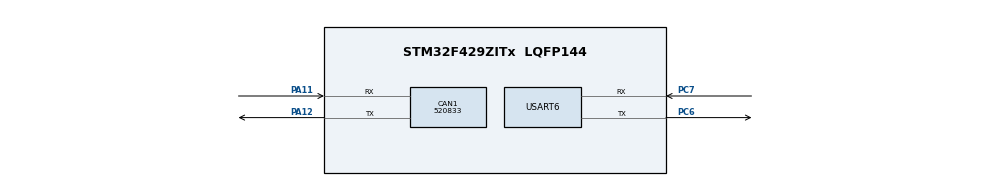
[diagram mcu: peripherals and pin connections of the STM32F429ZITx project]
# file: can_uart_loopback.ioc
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CAN1.BS1=CAN_BS1_1TQ
CAN1.BS2=CAN_BS2_1TQ
CAN1.CalculateBaudRate=520833
CAN1.CalculateTimeBit=1920
CAN1.CalculateTimeQuantum=640.0
CAN1.Mode=CAN_MODE_LOOPBACK
Mcu.Family=STM32F4
Mcu.Name=STM32F429ZITx
Mcu.Package=LQFP144
NVIC.CAN1_TX_IRQn=true\:0\:0\:false\:false\:true\:true\:true\:true
NVIC.PriorityGroup=NVIC_PRIORITYGROUP_4
PA11.Mode=CAN_Activate
PA11.Signal=CAN1_RX
PA12.Mode=CAN_Activate
PA12.Signal=CAN1_TX
PC6.Mode=Asynchronous
PC6.Signal=USART6_TX
PC7.Mode=Asynchronous
PC7.Signal=USART6_RX
ProjectManager.HeapSize=0x200
ProjectManager.StackSize=0x400
ProjectManager.TargetToolchain=STM32CubeIDE
RCC.48MHZClocksFreq_Value=33333333.333333332
RCC.AHBFreq_Value=50000000
RCC.APB1CLKDivider=RCC_HCLK_DIV2
RCC.APB1Freq_Value=25000000
RCC.APB1TimFreq_Value=50000000
RCC.APB2Freq_Value=50000000
RCC.APB2TimFreq_Value=50000000
RCC.CortexFreq_Value=50000000
RCC.HCLKFreq_Value=50000000
RCC.HSE_VALUE=8000000
RCC.HSI_VALUE=16000000
RCC.LSE_VALUE=32768
RCC.PLLM=8
RCC.PLLN=50
RCC.PLLQ=3
RCC.PLLSAIN=50
RCC.SYSCLKFreq_VALUE=50000000
RCC.SYSCLKSource=RCC_SYSCLKSOURCE_PLLCLK
RCC.VCOOutputFreq_Value=100000000
USART6.VirtualMode=VM_ASYNC
board=STM32F429I-DISC1

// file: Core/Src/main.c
/* USER CODE BEGIN Header */
/* USER CODE END Header */
#include "main.h"

/* USER CODE BEGIN Includes */
#include <stdio.h>
#include <string.h>
/* USER CODE END Includes */

CAN_HandleTypeDef hcan1;

UART_HandleTypeDef huart6;

/* USER CODE BEGIN PV */
CAN_HandleTypeDef     CanHandle;
CAN_TxHeaderTypeDef   TxHeader;
CAN_RxHeaderTypeDef   RxHeader;
uint8_t               TxData[8];
uint8_t               RxData[8];
uint32_t              TxMailbox;
/* USER CODE END PV */

void SystemClock_Config(void);
static void MX_GPIO_Init(void);
static void MX_CAN1_Init(void);
static void MX_USART6_UART_Init(void);

int main(void)
{

  /* MCU Configuration--------------------------------------------------------*/

  /* Reset of all peripherals, Initializes the Flash interface and the Systick. */
  HAL_Init();

  /* Configure the system clock */
  SystemClock_Config();

  /* Initialize all configured peripherals */
  MX_GPIO_Init();
  MX_CAN1_Init();
  MX_USART6_UART_Init();
  /* USER CODE BEGIN 2 */
   TxHeader.StdId = 0x11;
   TxHeader.RTR = CAN_RTR_DATA;
   TxHeader.IDE = CAN_ID_STD;
   TxHeader.DLC = 2;
   TxHeader.TransmitGlobalTime = DISABLE;
   TxData[0] = 0xCA;
   TxData[1] = 0xFE;

   /* Request transmission */
   if (HAL_CAN_AddTxMessage(&hcan1, &TxHeader, TxData, &TxMailbox) != HAL_OK)
   {
     Error_Handler();
   }

   /* Wait for transmission to complete */
   while (HAL_CAN_GetTxMailboxesFreeLevel(&hcan1) != 3) {}

   /* Wait for a message to be received */
   if (HAL_CAN_GetRxFifoFillLevel(&hcan1, CAN_RX_FIFO0) != 1)
   {
     Error_Handler();
   }

   /* Receive the CAN message */
   if (HAL_CAN_GetRxMessage(&hcan1, CAN_RX_FIFO0, &RxHeader, RxData) != HAL_OK)
   {
     Error_Handler();
   }

   /* Verify the received message */
   if ((RxHeader.StdId == 0x11) &&
       (RxHeader.DLC == 2) &&
       ((RxData[0] << 8 | RxData[1]) == 0xCAFE))
   {
     /* Send the received data over UART6 */
     char message[50];
     snprintf(message, sizeof(message), "CAN Received: 0x%X 0x%X\r\n", RxData[0], RxData[1]);
     HAL_UART_Transmit(&huart6, (uint8_t *)message, strlen(message), HAL_MAX_DELAY);

  /* USER CODE END 2 */

  /* Infinite loop */
     while (1)
      {
      }

   }
}

void SystemClock_Config(void)
{
	RCC_ClkInitTypeDef RCC_ClkInitStruct;
	  RCC_OscInitTypeDef RCC_OscInitStruct;
	  HAL_StatusTypeDef ret = HAL_OK;

	  /* Enable Power Control clock */
	  __HAL_RCC_PWR_CLK_ENABLE();

	  /* The voltage scaling allows optimizing the power consumption when the device is
	     clocked below the maximum system frequency, to update the voltage scaling value
	     regarding system frequency refer to product datasheet.  */
	  __HAL_PWR_VOLTAGESCALING_CONFIG(PWR_REGULATOR_VOLTAGE_SCALE1);

	  /* Enable HSE Oscillator and activate PLL with HSE as source */
	  RCC_OscInitStruct.OscillatorType = RCC_OSCILLATORTYPE_HSE;
	  RCC_OscInitStruct.HSEState = RCC_HSE_ON;
	  RCC_OscInitStruct.PLL.PLLState = RCC_PLL_ON;
	  RCC_OscInitStruct.PLL.PLLSource = RCC_PLLSOURCE_HSE;
	  RCC_OscInitStruct.PLL.PLLM = 8;
	  RCC_OscInitStruct.PLL.PLLN = 360;
	  RCC_OscInitStruct.PLL.PLLP = RCC_PLLP_DIV2;
	  RCC_OscInitStruct.PLL.PLLQ = 7;

	  ret = HAL_RCC_OscConfig(&RCC_OscInitStruct);
	  if(ret != HAL_OK)
	  {
	    while(1) { ; }
	  }

	  /* Activate the OverDrive to reach the 180 MHz Frequency */
	  ret = HAL_PWREx_EnableOverDrive();
	  if(ret != HAL_OK)
	  {
	    while(1) { ; }
	  }

	  /* Select PLL as system clock source and configure the HCLK, PCLK1 and PCLK2 clocks dividers */
	  RCC_ClkInitStruct.ClockType = (RCC_CLOCKTYPE_SYSCLK | RCC_CLOCKTYPE_HCLK | RCC_CLOCKTYPE_PCLK1 | RCC_CLOCKTYPE_PCLK2);
	  RCC_ClkInitStruct.SYSCLKSource = RCC_SYSCLKSOURCE_PLLCLK;
	  RCC_ClkInitStruct.AHBCLKDivider = RCC_SYSCLK_DIV1;
	  RCC_ClkInitStruct.APB1CLKDivider = RCC_HCLK_DIV4;
	  RCC_ClkInitStruct.APB2CLKDivider = RCC_HCLK_DIV2;

	  ret = HAL_RCC_ClockConfig(&RCC_ClkInitStruct, FLASH_LATENCY_5);
	  if(ret != HAL_OK)
	  {
	    while(1) { ; }
	  }
}

static void MX_CAN1_Init(void)
{
	CAN_FilterTypeDef sFilterConfig;

	  /* Configure CAN1 */
	  hcan1.Instance = CAN1;
	  hcan1.Init.TimeTriggeredMode = DISABLE;
	  hcan1.Init.AutoBusOff = DISABLE;
	  hcan1.Init.AutoWakeUp = DISABLE;
	  hcan1.Init.AutoRetransmission = ENABLE;
	  hcan1.Init.ReceiveFifoLocked = DISABLE;
	  hcan1.Init.TransmitFifoPriority = DISABLE;
	  hcan1.Init.Mode = CAN_MODE_LOOPBACK;
	  hcan1.Init.SyncJumpWidth = CAN_SJW_1TQ;
	  hcan1.Init.TimeSeg1 = CAN_BS1_6TQ;
	  hcan1.Init.TimeSeg2 = CAN_BS2_2TQ;
	  hcan1.Init.Prescaler = 5;

	  if (HAL_CAN_Init(&hcan1) != HAL_OK)
	  {
	    Error_Handler();
	  }

	  /* Configure the CAN filter */
	  sFilterConfig.FilterBank = 0;
	  sFilterConfig.FilterMode = CAN_FILTERMODE_IDMASK;
	  sFilterConfig.FilterScale = CAN_FILTERSCALE_32BIT;
	  sFilterConfig.FilterIdHigh = 0x0000;
	  sFilterConfig.FilterIdLow = 0x0000;
	  sFilterConfig.FilterMaskIdHigh = 0x0000;
	  sFilterConfig.FilterMaskIdLow = 0x0000;
	  sFilterConfig.FilterFIFOAssignment = CAN_RX_FIFO0;
	  sFilterConfig.FilterActivation = ENABLE;

	  if (HAL_CAN_ConfigFilter(&hcan1, &sFilterConfig) != HAL_OK)
	  {
	    Error_Handler();
	  }

	  /* Start the CAN module */
	  if (HAL_CAN_Start(&hcan1) != HAL_OK)
	  {
	    Error_Handler();
	  }

}

static void MX_USART6_UART_Init(void)
{

	/* Configure USART6 */
	  huart6.Instance = USART6;
	  huart6.Init.BaudRate = 115200;
	  huart6.Init.WordLength = UART_WORDLENGTH_8B;
	  huart6.Init.StopBits = UART_STOPBITS_1;
	  huart6.Init.Parity = UART_PARITY_NONE;
	  huart6.Init.Mode = UART_MODE_TX_RX;
	  huart6.Init.HwFlowCtl = UART_HWCONTROL_NONE;
	  huart6.Init.OverSampling = UART_OVERSAMPLING_16;

	  if (HAL_UART_Init(&huart6) != HAL_OK)
	  {
	    Error_Handler();
	  }
}

static void MX_GPIO_Init(void)
{

  /* GPIO Ports Clock Enable */
  __HAL_RCC_GPIOC_CLK_ENABLE();
  __HAL_RCC_GPIOA_CLK_ENABLE();

}

void Error_Handler(void)
{
}
